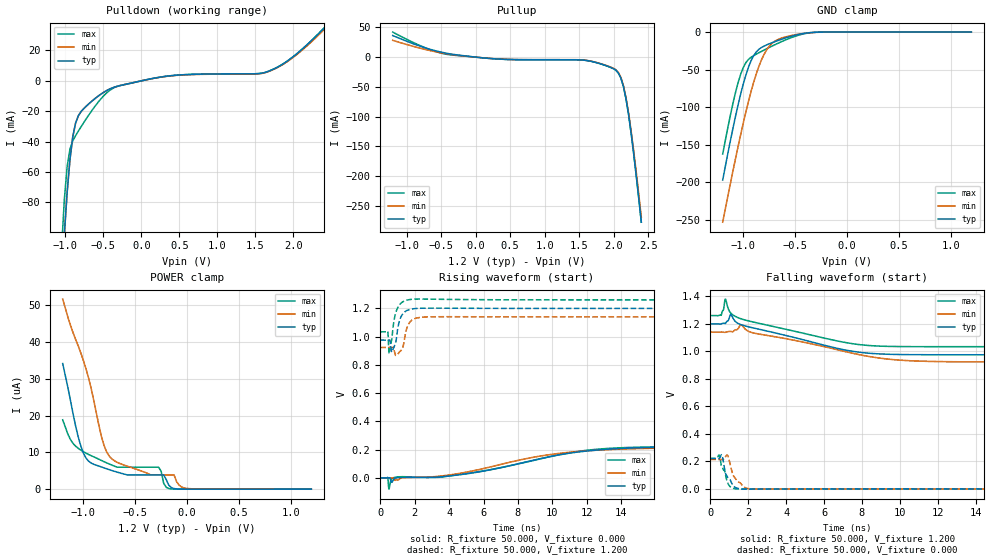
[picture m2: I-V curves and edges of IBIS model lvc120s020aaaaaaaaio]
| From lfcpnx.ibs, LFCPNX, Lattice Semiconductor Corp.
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[Model] lvc120s020aaaaaaaaio
Model_type I/O
Polarity   Non-Inverting
Enable   Active-Low
Vinl =  0.420V
Vinh =  0.780V
Vmeas =  0.600V
Cref =  0.0F
Rref =  1.000M
Vref =  0.0V
C_comp   5.000pF   4.000pF   5.500pF
[Temperature Range]   25.000   0.125k   -40.000
[Voltage Range]   1.200V   1.140V   1.260V
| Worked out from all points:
|   slope of the pulldown table from 0 to 0.18 V, typ, clamps not added: 97.6 ohm
|   slope of the pullup table from 0 to 0.18 V, typ, clamps not added: 88.3 ohm
|   GND clamp passes 1 mA (typ) near -0.37 V on its own axis
|   rising waveform, R_fixture 50.000, V_fixture 0.000: 20-80 % time 5.3ns typ, 5.17ns min, 5.23ns max; typ from 0 V to 0.221 V
|   rising waveform, R_fixture 50.000, V_fixture 1.200: 20-80 % time 300ps typ, 295ps min, 300ps max; typ from 0.975 V to 1.2 V
|   falling waveform, R_fixture 50.000, V_fixture 1.200: 20-80 % time 3.99ns typ, 4.41ns min, 4.36ns max; typ from 1.2 V to 0.975 V
|   falling waveform, R_fixture 50.000, V_fixture 0.000: 20-80 % time 406ps typ, 523ps min, 347ps max; typ from 0.221 V to 0 V
[GND_clamp]
|Voltage   I(typ)   I(min)   I(max)
-1.2V     -197mA     -253.2mA   -162.4mA
-1.125V   -144.2mA   -201.1mA   -110.1mA
-1.05V    -95.99mA   -151.4mA   -66.59mA
-1V       -68.36mA   -120.3mA   -46.7mA
-950mV    -46.27mA   -91.66mA   -36.22mA
-900mV    -31.17mA   -66.32mA   -31.23mA
-825mV    -20.42mA   -36.76mA   -25.67mA
-775mV    -17.01mA   -23.52mA   -22.16mA
-700mV    -12.93mA   -12.4mA    -17.08mA
-550mV    -6.031mA   -4.974mA   -8.039mA
-325mV    -407uA     -583.3uA   -420.6uA
1.2V      0A         0A         0A
[POWER_clamp]
|Voltage   I(typ)   I(min)   I(max)
-1.2V     34.12uA    51.64uA    18.84uA
-1.125V   24.08uA    44.51uA    13.48uA
-1.05V    14.15uA    38.9uA     11.09uA
-1V       9.797uA    34.91uA    10.18uA
-925mV    7.083uA    27.3uA     9.093uA
-825mV    6.019uA    14.19uA    7.781uA
-725mV    5.062uA    8.208uA    6.524uA
-275mV    3.872uA    3.86uA     5.968uA
-200mV    2.568uA    3.86uA     486.4nA
-150mV    410.4nA    3.86uA     46.48nA
0V        5.44nA     194.2nA    358.2pA
1.2V      0A         0A         0A
[Pulldown]
|Voltage   I(typ)   I(min)   I(max)
-1.2V     -291.4mA   -291.4mA   -309.1mA
-1.052V   -133.7mA   -133.7mA   -111mA
-1.015V   -101mA     -101mA     -78.13mA
-978mV    -73.37mA   -73.37mA   -56.36mA
-941mV    -51.83mA   -51.83mA   -44.93mA
-904mV    -36.89mA   -36.89mA   -39.52mA
-830mV    -22.91mA   -22.91mA   -33.01mA
-534mV    -8.79mA    -8.79mA    -11.89mA
-312mV    -3.504mA   -3.504mA   -3.577mA
243mV     2.389mA    2.317mA    2.389mA
1.612V    5.288mA    5.129mA    5.288mA
2.4V      34.47mA    33.43mA    34.47mA
[Pullup]
|Voltage   I(typ)   I(min)   I(max)
-1.2V     36.33mA    28.25mA    42.13mA
-745mV    16.17mA    13.34mA    16.53mA
-412mV    6.26mA     5.639mA    4.545mA
365mV     -3.465mA   -3.361mA   -3.465mA
1.549V    -4.954mA   -4.806mA   -4.954mA
2.03V     -21.89mA   -21.23mA   -21.89mA
2.104V    -35.19mA   -34.14mA   -35.19mA
2.141V    -49.43mA   -47.94mA   -49.43mA
2.178V    -69.96mA   -67.86mA   -69.96mA
2.215V    -96.3mA    -93.4mA    -96.3mA
2.289V    -162.1mA   -157.2mA   -162.1mA
2.4V      -277.9mA   -269.6mA   -277.9mA
[Ramp]
| variable   typ   min   max
dV/dt_r   0.133/5.402n   0.133/5.240n   0.133/5.329n
dV/dt_f   0.135/3.994n   0.130/4.414n   0.136/4.358n
R_load = 50.000
[Rising Waveform]
R_fixture = 50.000
V_fixture = 0.000
V_fixture_min = 0.000
V_fixture_max = 0.000
|  time   V(typ)   V(min)   V(max)
0s        24.94uV    -55.39uV   195.5uV
430ps     51.44uV    -176.3uV   3.184mV
504ps     14.05uV    -76.34uV   -80.32mV
643ps     -30.63mV   17.19uV    -11.12mV
855ps     -2.457mV   -17.33mV   3.521mV
3.643ns   8.516mV    14.33mV    6.479mV
6.04ns    48.42mV    66.92mV    50.26mV
9.01ns    127.9mV    148.2mV    125.7mV
11.92ns   188.8mV    190.4mV    194mV
20ns      221.1mV    214.2mV    221.4mV
[Rising Waveform]
R_fixture = 50.000
V_fixture = 1.200
V_fixture_min = 1.140
V_fixture_max = 1.260
|  time   V(typ)   V(min)   V(max)
0s        975.3mV    923.2mV    1.034V
431ps     975.3mV    923.1mV    1.038V
519ps     975.3mV    923.2mV    879mV
677ps     890mV      923.2mV    991.2mV
804ps     928.1mV    905.9mV    1.117V
955ps     1.003V     868.5mV    1.189V
1.237ns   1.147V     906.7mV    1.24V
1.546ns   1.185V     1.061V     1.258V
1.775ns   1.194V     1.11V      1.264V
20ns      1.2V       1.14V      1.26V
[Falling Waveform]
R_fixture = 50.000
V_fixture = 1.200
V_fixture_min = 1.140
V_fixture_max = 1.260
|  time   V(typ)   V(min)   V(max)
0s        1.2V       1.14V      1.26V
574ps     1.2V       1.14V      1.262V
704ps     1.205V     1.139V     1.307V
794ps     1.202V     1.138V     1.38V
1.08ns    1.267V     1.144V     1.278V
1.639ns   1.193V     1.192V     1.236V
2.202ns   1.172V     1.136V     1.215V
7.82ns    994.2mV    977mV      1.05V
11.52ns   975.4mV    926.9mV    1.034V
20ns      975.3mV    923.2mV    1.034V
[Falling Waveform]
R_fixture = 50.000
V_fixture = 0.000
V_fixture_min = 0.000
V_fixture_max = 0.000
|  time   V(typ)   V(min)   V(max)
0s        221.1mV    214.2mV    221.4mV
459ps     220.2mV    214.2mV    246.4mV
610ps     248mV      213.6mV    165mV
790ps     120.1mV    230mV      112.8mV
903ps     87.67mV    245.2mV    49.76mV
1.19ns    27.37mV    103.7mV    4.785mV
1.413ns   5.141mV    59.35mV    -636uV
1.853ns   -693.8uV   8.301mV    -1.816mV
2.333ns   -882.6uV   -637.4uV   -1.512mV
20ns      24.94uV    -55.39uV   195.5uV
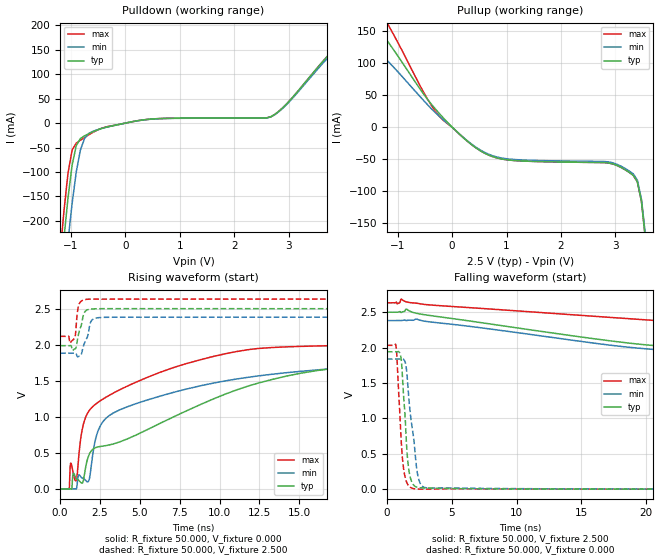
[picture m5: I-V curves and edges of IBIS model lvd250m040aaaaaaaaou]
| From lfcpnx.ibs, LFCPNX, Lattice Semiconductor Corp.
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[Model] lvd250m040aaaaaaaaou
Model_type Output
Polarity   Non-Inverting
Enable   Active-High
Vmeas =  1.250V
Cref =  0.0F
Rref =  1.000M
Vref =  0.0V
C_comp   5.000pF   4.000pF   5.500pF
[Temperature Range]   25.000   0.125k   -40.000
[Voltage Range]   2.500V   2.380V   2.630V
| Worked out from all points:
|   slope of the pulldown table from 0 to 0.375 V, typ, clamps not added: 52.3 ohm
|   slope of the pullup table from 0 to 0.375 V, typ, clamps not added: 13.2 ohm
|   rising waveform, R_fixture 50.000, V_fixture 0.000: 20-80 % time 12ns typ, 7.72ns min, 5.22ns max; typ from 0.001 V to 1.92 V
|   rising waveform, R_fixture 50.000, V_fixture 2.500: 20-80 % time 342ps typ, 406ps min, 152ps max; typ from 1.99 V to 2.5 V
|   falling waveform, R_fixture 50.000, V_fixture 2.500: 20-80 % time 11.9ns typ, 12.9ns min, 24.3ns max; typ from 2.5 V to 1.99 V
|   falling waveform, R_fixture 50.000, V_fixture 0.000: 20-80 % time 406ps typ, 634ps min, 379ps max; typ from 1.94 V to 0.001 V
[Pulldown]
|Voltage   I(typ)   I(min)   I(max)
-2.5V     -2.087A    -2.05A     -2.122A
-1.208V   -330.7mA   -414.1mA   -277.2mA
-1.132V   -238.1mA   -325.6mA   -182.4mA
-1.056V   -153.6mA   -241.4mA   -102.6mA
-980mV    -86mA      -164.4mA   -55.18mA
-904mV    -46.21mA   -100mA     -41.14mA
-752mV    -26.2mA    -31.37mA   -29.5mA
-600mV    -17.96mA   -17.01mA   -19.2mA
464mV     8.134mA    7.89mA     8.134mA
2.668V    12.76mA    12.38mA    12.76mA
4.112V    178.7mA    173.3mA    178.7mA
5V        197.1mA    191.2mA    197.1mA
[Pullup]
|Voltage   I(typ)   I(min)   I(max)
-2.5V     189.4mA    141.7mA    232mA
-1.84V    186.8mA    140.8mA    228.1mA
-1.384V   155.4mA    119.1mA    188.3mA
-1.156V   130.2mA    100.6mA    156.5mA
-320mV    29.46mA    23.51mA    26.02mA
592mV     -40.38mA   -39.17mA   -40.38mA
1.124V    -51.9mA    -50.35mA   -51.9mA
2.948V    -57.25mA   -55.53mA   -57.25mA
3.404V    -85.21mA   -82.65mA   -85.21mA
3.48V     -116.2mA   -112.7mA   -116.2mA
3.556V    -176.5mA   -171.2mA   -176.5mA
5V        -2.101A    -2.038A    -2.101A
[Ramp]
| variable   typ   min   max
dV/dt_r   1.154/11.967n   1.103/7.727n   1.219/5.294n
dV/dt_f   0.308/11.994n   0.313/13.083n   0.310/24.253n
R_load = 50.000
[Rising Waveform]
R_fixture = 50.000
V_fixture = 0.000
V_fixture_min = 0.000
V_fixture_max = 0.000
|  time   V(typ)   V(min)   V(max)
0s        531.4uV    878.5uV    348.5uV
570ps     700.4uV    911.2uV    2.05mV
670ps     1.336mV    602.2uV    358.2mV
1.01ns    136.7mV    413.3uV    113.3mV
1.39ns    79.99mV    151mV      831.9mV
1.8ns     466mV      114.5mV    1.079V
2.52ns    588.9mV    875.6mV    1.223V
13.3ns    1.518V     1.591V     1.962V
39.57ns   1.904V     1.807V     2.011V
200ns     1.924V     1.839V     2.032V
[Rising Waveform]
R_fixture = 50.000
V_fixture = 2.500
V_fixture_min = 2.380
V_fixture_max = 2.630
|  time   V(typ)   V(min)   V(max)
0s        1.987V     1.882V     2.117V
540ps     1.987V     1.882V     2.117V
620ps     1.987V     1.882V     2.023V
910ps     1.942V     1.883V     2.096V
960ps     1.945V     1.883V     2.14V
1.1ns     2.088V     1.833V     2.478V
1.28ns    2.242V     1.848V     2.595V
1.54ns    2.454V     2.03V      2.625V
2.01ns    2.496V     2.345V     2.633V
200ns     2.5V       2.382V     2.633V
[Falling Waveform]
R_fixture = 50.000
V_fixture = 2.500
V_fixture_min = 2.380
V_fixture_max = 2.630
|  time   V(typ)   V(min)   V(max)
0s        2.5V       2.382V     2.633V
800ps     2.5V       2.382V     2.619V
1.1ns     2.496V     2.382V     2.686V
1.5ns     2.544V     2.382V     2.646V
2.86ns    2.465V     2.375V     2.611V
16.9ns    2.103V     2.041V     2.431V
25.5ns    1.991V     1.926V     2.321V
38.87ns   1.987V     1.884V     2.16V
47.58ns   1.987V     1.883V     2.119V
200ns     1.987V     1.882V     2.117V
[Falling Waveform]
R_fixture = 50.000
V_fixture = 0.000
V_fixture_min = 0.000
V_fixture_max = 0.000
|  time   V(typ)   V(min)   V(max)
0s        1.941V     1.839V     2.032V
700ps     1.941V     1.839V     2.026V
1.1ns     1.841V     1.839V     698.2mV
1.42ns    978.1mV    1.79V      160.2mV
1.56ns    507.5mV    1.601V     83.55mV
1.74ns    222.3mV    1.187V     35.27mV
2.3ns     28.6mV     291.1mV    2.224mV
2.67ns    18.84mV    53.48mV    275.2uV
3.28ns    15.12mV    16.14mV    401uV
200ns     531.9uV    878.5uV    348.5uV
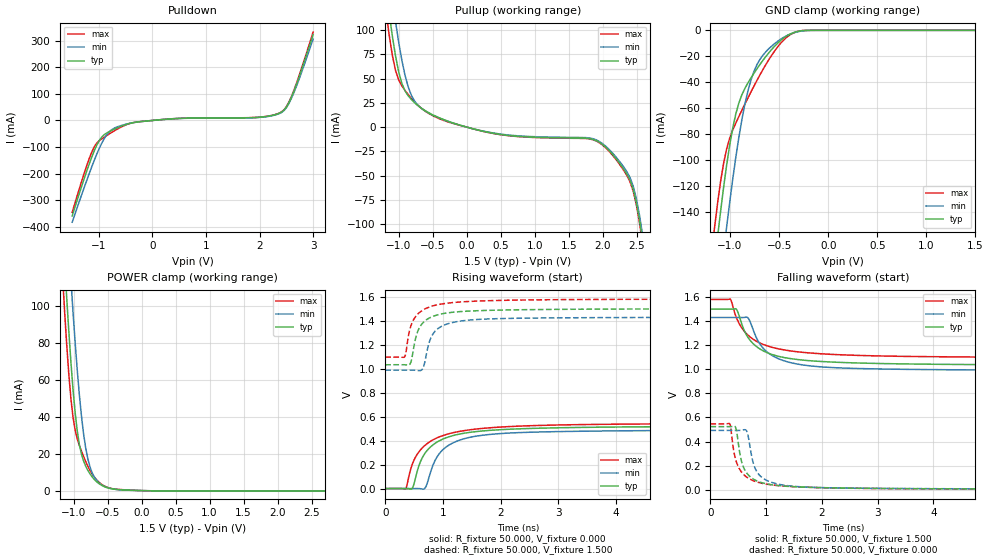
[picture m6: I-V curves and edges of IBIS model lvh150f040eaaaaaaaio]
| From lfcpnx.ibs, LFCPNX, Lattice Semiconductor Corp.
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[Model] lvh150f040eaaaaaaaio
Model_type I/O
Polarity   Non-Inverting
Enable   Active-Low
Vinl =  0.375V
Vinh =  1.125V
Vmeas =  0.750V
Cref =  0.0F
Rref =  1.000M
Vref =  0.0V
C_comp   5.000pF   4.000pF   5.500pF
[Temperature Range]   25.000   0.125k   -40.000
[Voltage Range]   1.500V   1.430V   1.580V
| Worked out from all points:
|   slope of the pulldown table from 0 to 0.225 V, typ, clamps not added: 54.8 ohm
|   slope of the pullup table from 0 to 0.225 V, typ, clamps not added: 56 ohm
|   GND clamp passes 1 mA (typ) near -0.32 V on its own axis
|   POWER clamp passes 1 mA (typ) near -0.45 V on its own axis
|   rising waveform, R_fixture 50.000, V_fixture 0.000: 20-80 % time 484ps typ, 460ps min, 544ps max; typ from 0.005 V to 0.524 V
|   rising waveform, R_fixture 50.000, V_fixture 1.500: 20-80 % time 234ps typ, 239ps min, 259ps max; typ from 1.03 V to 1.5 V
|   falling waveform, R_fixture 50.000, V_fixture 1.500: 20-80 % time 536ps typ, 520ps min, 594ps max; typ from 1.5 V to 1.03 V
|   falling waveform, R_fixture 50.000, V_fixture 0.000: 20-80 % time 220ps typ, 226ps min, 243ps max; typ from 0.524 V to 0.005 V
[GND_clamp]
|Voltage   I(typ)   I(min)   I(max)
-1.5V     -437mA     -482.5mA   -410.7mA
-1.159V   -180.3mA   -233.3mA   -152.2mA
-1.128V   -159.5mA   -212mA     -133.3mA
-1.097V   -139.6mA   -191.2mA   -116.5mA
-1.035V   -103.7mA   -151.3mA   -91.23mA
-973mV    -75.24mA   -114.6mA   -76.75mA
-911mV    -56.05mA   -82.58mA   -66.41mA
-787mV    -36.61mA   -38.2mA    -47.39mA
-663mV    -22.9mA    -18.92mA   -29.92mA
-477mV    -7.274mA   -6.461mA   -9.278mA
-260mV    -227.6uA   -429.8uA   -148.6uA
1.5V      0A         0A         0A
[POWER_clamp]
|Voltage   I(typ)   I(min)   I(max)
-1.5V     391.3mA    429.6mA    369.7mA
-1.166V   144.6mA    192.2mA    117.1mA
-1.135V   124.2mA    171.8mA    97.3mA
-1.104V   104.7mA    152mA      79.15mA
-1.042V   69.75mA    114.3mA    49.91mA
-1.011V   54.95mA    96.78mA    39.84mA
-949mV    32.47mA    65.46mA    28.02mA
-887mV    19.82mA    40.53mA    21.37mA
-825mV    13.31mA    23.23mA    15.79mA
-732mV    7.53mA     9.888mA    9.145mA
-608mV    3.278mA    3.592mA    3.895mA
3V        -183uA     -190.7uA   -185.3uA
[Pulldown]
|Voltage   I(typ)   I(min)   I(max)
-1.5V     -358.2mA   -381.8mA   -344.9mA
-1.224V   -187.6mA   -222.6mA   -167mA
-1.086V   -112.9mA   -148.8mA   -98.5mA
-948mV    -62.28mA   -85.2mA    -69.02mA
-764mV    -37.5mA    -35.09mA   -45.15mA
-258mV    -5.249mA   -5.157mA   -4.87mA
1.95V     11.37mA    10.8mA     11.71mA
2.364V    26.55mA    25.22mA    27.35mA
2.502V    50.62mA    48.08mA    52.13mA
2.594V    86.8mA     82.5mA     89.4mA
2.732V    159.4mA    151.4mA    164.2mA
3V        321.9mA    305.8mA    331.6mA
[Pullup]
|Voltage   I(typ)   I(min)   I(max)
-1.5V     334.2mA    366.8mA    315.2mA
-1.186V   140.5mA    179.9mA    117.2mA
-1.14V    115.6mA    154.7mA    93.3mA
-1.048V   72.68mA    107.9mA    57.95mA
-956mV    44.92mA    68.74mA    42.37mA
-864mV    32.38mA    41.6mA     33.55mA
-588mV    15.88mA    15.55mA    15.32mA
424mV     -6.746mA   -6.408mA   -6.948mA
1.896V    -13.58mA   -12.9mA    -13.99mA
2.402V    -54.62mA   -51.89mA   -56.26mA
2.586V    -116.3mA   -110.5mA   -119.8mA
3V        -369.7mA   -351.2mA   -380.8mA
[Ramp]
| variable   typ   min   max
dV/dt_r   0.311/0.493n   0.292/0.462n   0.332/0.551n
dV/dt_f   0.280/0.532n   0.264/0.520n   0.290/0.596n
R_load = 50.000
[Rising Waveform]
R_fixture = 50.000
V_fixture = 0.000
V_fixture_min = 0.000
V_fixture_max = 0.000
|  time   V(typ)   V(min)   V(max)
0s        4.663mV    4.769mV    4.349mV
351ps     4.928mV    4.827mV    1.294mV
457ps     1.861mV    4.813mV    191.3mV
597ps     213.2mV    4.245mV    318.6mV
677ps     290.3mV    3.446mV    359.2mV
856ps     378.3mV    231.4mV    417.1mV
988ps     413.9mV    323.1mV    443.7mV
1.557ns   477.6mV    439mV      498.6mV
3.321ns   512.7mV    480.9mV    536.2mV
10ns      523.5mV    492.3mV    546.5mV
[Rising Waveform]
R_fixture = 50.000
V_fixture = 1.500
V_fixture_min = 1.430
V_fixture_max = 1.580
|  time   V(typ)   V(min)   V(max)
0s        1.034V     989.4mV    1.097V
336ps     1.034V     989.5mV    1.101V
424ps     1.038V     989.5mV    1.326V
537ps     1.275V     988.1mV    1.442V
627ps     1.369V     990mV      1.481V
766ps     1.423V     1.227V     1.515V
827ps     1.437V     1.291V     1.524V
1.156ns   1.47V      1.384V     1.55V
2.427ns   1.492V     1.422V     1.573V
10ns      1.5V       1.43V      1.58V
[Falling Waveform]
R_fixture = 50.000
V_fixture = 1.500
V_fixture_min = 1.430
V_fixture_max = 1.580
|  time   V(typ)   V(min)   V(max)
0s        1.5V       1.43V      1.58V
356ps     1.5V       1.43V      1.582V
477ps     1.49V      1.43V      1.417V
657ps     1.277V     1.432V     1.291V
857ps     1.178V     1.233V     1.225V
987ps     1.144V     1.155V     1.199V
1.246ns   1.105V     1.083V     1.167V
1.619ns   1.078V     1.039V     1.142V
3.416ns   1.045V     999.8mV    1.107V
10ns      1.034V     989.4mV    1.097V
[Falling Waveform]
R_fixture = 50.000
V_fixture = 0.000
V_fixture_min = 0.000
V_fixture_max = 0.000
|  time   V(typ)   V(min)   V(max)
0s        523.5mV    492.3mV    546.5mV
346ps     523.2mV    492mV      547.1mV
444ps     523.6mV    492.2mV    265.5mV
547ps     255mV      493.1mV    153.2mV
637ps     147.4mV    495mV      109.2mV
757ps     92mV       241.4mV    76.83mV
817ps     76.38mV    162.2mV    66.45mV
1.137ns   38.39mV    55.03mV    37.78mV
2.407ns   13.61mV    13.6mV     12.6mV
10ns      4.663mV    4.769mV    4.349mV
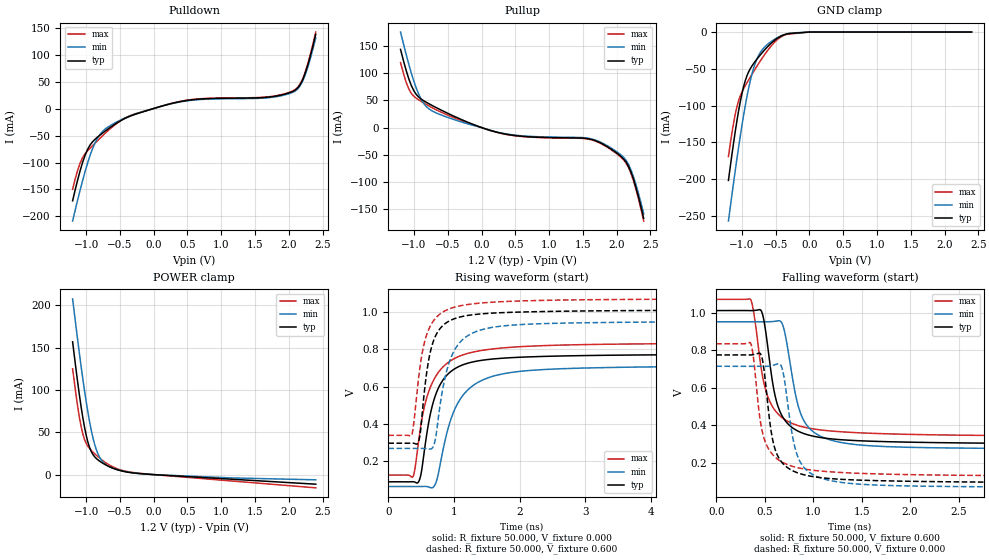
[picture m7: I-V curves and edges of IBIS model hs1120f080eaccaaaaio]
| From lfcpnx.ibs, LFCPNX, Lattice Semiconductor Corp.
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|Model hs1120f080eaccaaaaio
[Model] hs1120f080eaccaaaaio
| Clamp models do not include dynamic input termination. Please refer to
| the hs1120axxxeaccaaaain model for input termination.
Model_type I/O
Polarity   Non-Inverting
Enable   Active-Low
Vinl =  0.500V
Vinh =  0.700V
Vmeas =  0.600V
Cref =  20.000pF
Rref =  50.000
Vref =  0.600V
C_comp   5.000pF   4.000pF   5.500pF
[Temperature Range]   25.000   0.125k   -40.000
[Voltage Range]   1.200V   1.140V   1.260V
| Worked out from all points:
|   slope of the pulldown table from 0 to 0.18 V, typ, clamps not added: 27.4 ohm
|   slope of the pullup table from 0 to 0.18 V, typ, clamps not added: 25.5 ohm
|   GND clamp passes 1 mA (typ) near -0.14 V on its own axis
|   POWER clamp passes 1 mA (typ) near -0.17 V on its own axis
|   rising waveform, R_fixture 50.000, V_fixture 0.000: 20-80 % time 298ps typ, 419ps min, 351ps max; typ from 0.091 V to 0.775 V
|   rising waveform, R_fixture 50.000, V_fixture 0.600: 20-80 % time 202ps typ, 289ps min, 226ps max; typ from 0.298 V to 1.01 V
|   falling waveform, R_fixture 50.000, V_fixture 0.600: 20-80 % time 171ps typ, 190ps min, 188ps max; typ from 1.01 V to 0.298 V
|   falling waveform, R_fixture 50.000, V_fixture 0.000: 20-80 % time 137ps typ, 156ps min, 148ps max; typ from 0.775 V to 0.091 V
[Pulldown]
|Voltage   I(typ)   I(min)   I(max)
-1.2V     -171mA     -208.4mA   -149.8mA
-1.089V   -115.3mA   -151.3mA   -101.1mA
-978mV    -75.7mA    -101mA     -78.43mA
-867mV    -56.88mA   -63.48mA   -64.1mA
-719mV    -41.92mA   -38.16mA   -46.06mA
-386mV    -16.16mA   -15.49mA   -15.15mA
317mV     10.85mA    10.31mA    11.18mA
1.686V    20.95mA    19.91mA    21.58mA
2.056V    31.4mA     29.83mA    32.34mA
2.204V    52.73mA    50.09mA    54.31mA
2.278V    78.8mA     74.9mA     81.2mA
2.4V      137.6mA    130.7mA    141.7mA
[Pullup]
|Voltage   I(typ)   I(min)   I(max)
-1.2V     143.8mA    175.7mA    119.5mA
-1.115V   104.4mA    133.7mA    82.8mA
-1.004V   67.92mA    85.7mA     57.67mA
-893mV    52.22mA    51.65mA    48.03mA
-782mV    43.96mA    34.65mA    39.94mA
-227mV    10.98mA    7.588mA    9.596mA
254mV     -9.406mA   -8.935mA   -9.688mA
1.512V    -19.59mA   -18.61mA   -20.17mA
1.771V    -28.88mA   -27.43mA   -29.74mA
2.141V    -63.74mA   -60.55mA   -65.65mA
2.252V    -96.2mA    -91.4mA    -99.1mA
2.4V      -166.9mA   -158.6mA   -171.9mA
[GND_clamp]
|Voltage   I(typ)   I(min)   I(max)
-1.2V     -201.8mA   -257mA     -169.4mA
-1.125V   -151.4mA   -205.6mA   -124.4mA
-1.05V    -107.4mA   -157mA     -93.36mA
-975mV    -74.07mA   -112.9mA   -77.04mA
-925mV    -59.28mA   -87.24mA   -68.87mA
-875mV    -49.6mA    -65.58mA   -61.06mA
-825mV    -42.58mA   -48.49mA   -53.44mA
-750mV    -33.57mA   -31.23mA   -42.41mA
-600mV    -18.06mA   -15.21mA   -22.68mA
-375mV    -3.74mA    -3.594mA   -4.332mA
0V        0A         0A         0A
2.4V      0A         0A         0A
[POWER_clamp]
|Voltage   I(typ)   I(min)   I(max)
-1.2V     156.9mA    207.6mA    125mA
-1.125V   109.1mA    159mA      80.51mA
-1.075V   80.57mA    128.3mA    57.13mA
-1.025V   56.63mA    99.87mA    41.73mA
-975mV    38.74mA    74.4mA     33.51mA
-900mV    23.86mA    43.88mA    26.68mA
-850mV    19.08mA    29.7mA     22.97mA
-775mV    14.57mA    17.25mA    17.9mA
-700mV    11.09mA    11.42mA    13.53mA
-450mV    3.875mA    4.163mA    4.676mA
-125mV    735.3uA    624.3uA    974.1uA
2.4V      -11.3mA    -6.156mA   -15.63mA
[Ramp]
| variable   typ   min   max
dV/dt_r   0.410/0.301n   0.383/0.423n   0.425/0.357n
dV/dt_f   0.388/0.249n   0.375/0.265n   0.390/0.295n
R_load = 50.000
[Rising Waveform]
R_fixture = 50.000
V_fixture = 0.000
V_fixture_min = 0.000
V_fixture_max = 0.000
|  time   V(typ)   V(min)   V(max)
0s        90.91mV    65.64mV    126.8mV
371ps     91.54mV    65.65mV    117.2mV
457ps     89.22mV    65.68mV    299.8mV
497ps     132.2mV    65.83mV    398.5mV
554ps     271.9mV    66.21mV    500.9mV
697ps     533.1mV    67.07mV    641.1mV
987ps     691.2mV    459.5mV    748mV
1.317ns   735.6mV    613.5mV    788.1mV
2.62ns    765.1mV    696.7mV    823.5mV
10ns      775mV      714.3mV    834.4mV
[Rising Waveform]
R_fixture = 50.000
V_fixture = 0.600
V_fixture_min = 0.571
V_fixture_max = 0.631
|  time   V(typ)   V(min)   V(max)
0s        297.8mV    269.9mV    339.8mV
354ps     298.1mV    269.9mV    341mV
457ps     303.2mV    270mV      635.4mV
547ps     569.6mV    269.8mV    833.4mV
677ps     835.5mV    275.7mV    948.2mV
886ps     943.9mV    682.5mV    1.011V
1.087ns   973.6mV    836.9mV    1.034V
1.496ns   992.9mV    912.6mV    1.051V
2.337ns   1.003V     938.3mV    1.063V
10ns      1.012V     951.7mV    1.071V
[Falling Waveform]
R_fixture = 50.000
V_fixture = 0.600
V_fixture_min = 0.571
V_fixture_max = 0.631
|  time   V(typ)   V(min)   V(max)
0s        1.012V     951.7mV    1.071V
356ps     1.011V     951.6mV    1.069V
467ps     1.008V     951.6mV    691.6mV
520ps     862.3mV    951.5mV    570mV
598ps     578.9mV    953.9mV    484.8mV
671ps     457.4mV    950.2mV    443.6mV
860ps     364.3mV    477.9mV    395.5mV
1.03ns    338.3mV    354.1mV    377.9mV
2.23ns    307.3mV    279.6mV    348.7mV
10ns      297.8mV    269.9mV    339.8mV
[Falling Waveform]
R_fixture = 50.000
V_fixture = 0.000
V_fixture_min = 0.000
V_fixture_max = 0.000
|  time   V(typ)   V(min)   V(max)
0s        775mV      714.3mV    834.4mV
356ps     774.8mV    714mV      836.1mV
456ps     781.3mV    714.2mV    417.4mV
486ps     720.2mV    713.8mV    342.6mV
576ps     337.2mV    718.4mV    246.5mV
660ps     213.1mV    724.5mV    208.8mV
822ps     149.1mV    261.6mV    175.3mV
970ps     128.1mV    144.7mV    161.4mV
2.142ns   99.51mV    74.41mV    134.9mV
10ns      90.91mV    65.64mV    126.8mV
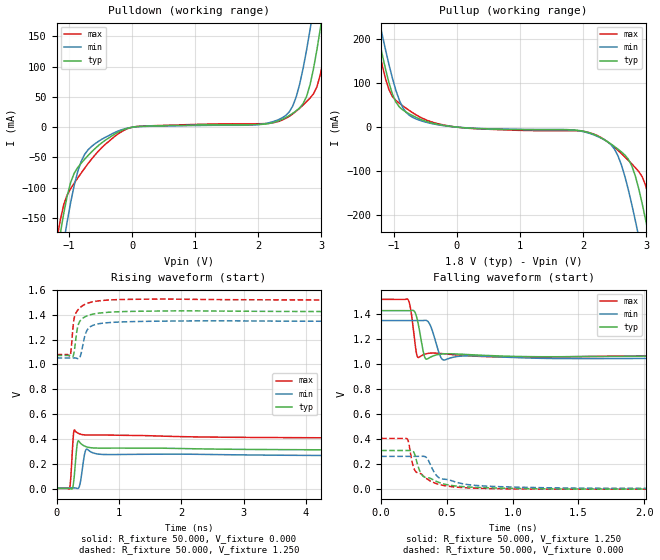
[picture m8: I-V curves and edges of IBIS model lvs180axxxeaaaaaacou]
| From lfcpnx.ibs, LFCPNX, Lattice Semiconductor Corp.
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[Model] lvs180axxxeaaaaaacou
Model_type Output
Polarity   Non-Inverting
Enable   Active-High
Vmeas =  1.250V
Cref =  3.000pF
Rref =  50.000
Vref =  1.250V
C_comp   5.000pF   4.000pF   5.500pF
[Temperature Range]   25.000   0.125k   -40.000
[Voltage Range]   1.800V   1.710V   1.890V
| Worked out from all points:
|   slope of the pulldown table from 0 to 0.27 V, typ, clamps not added: 142 ohm
|   slope of the pullup table from 0 to 0.27 V, typ, clamps not added: 91.7 ohm
|   rising waveform, R_fixture 50.000, V_fixture 0.000: 20-80 % time 32.3ps typ, 44ps min, 28.4ps max; typ from 0.004 V to 0.309 V
|   rising waveform, R_fixture 50.000, V_fixture 1.250: 20-80 % time 89ps typ, 100ps min, 87.7ps max; typ from 1.07 V to 1.42 V
|   falling waveform, R_fixture 50.000, V_fixture 1.250: 20-80 % time 37.5ps typ, 51.3ps min, 31.9ps max; typ from 1.42 V to 1.07 V
|   falling waveform, R_fixture 50.000, V_fixture 0.000: 20-80 % time 155ps typ, 200ps min, 132ps max; typ from 0.309 V to 0.003 V
[Pulldown]
|Voltage   I(typ)   I(min)   I(max)
-1.8V     -681.2mA   -716.3mA   -662.4mA
-1.195V   -212.7mA   -264mA     -185.8mA
-1.085V   -141.9mA   -189.7mA   -127.6mA
-975mV    -90.96mA   -123.8mA   -101.3mA
-755mV    -53.04mA   -45.02mA   -67.87mA
-150mV    -4.68mA    -3.708mA   -6.333mA
2.49V     19.13mA    25.2mA     17.88mA
2.655V    31.84mA    70.95mA    31.23mA
2.82V     70.16mA    161mA      48.03mA
2.985V    164.3mA    271.4mA    87.85mA
3.15V     282.5mA    389.7mA    190.9mA
3.6V      631.9mA    726.6mA    545.1mA
[Pullup]
|Voltage   I(typ)   I(min)   I(max)
-1.8V     633.7mA    660.1mA    620.6mA
-1.35V    284.7mA    326.6mA    260.5mA
-1.24V    204.9mA    249.2mA    179.6mA
-1.02V    75.12mA    110.9mA    69.42mA
-745mV    29.49mA    26.13mA    37.05mA
25mV      -288.8uA   -173.9uA   -376.6uA
2.17V     -16.09mA   -17.47mA   -15.69mA
2.555V    -49.99mA   -64.93mA   -52.72mA
2.885V    -139.9mA   -249mA     -100.7mA
2.995V    -211.2mA   -327mA     -132.9mA
3.16V     -332.6mA   -448.7mA   -236.3mA
3.6V      -680.1mA   -784.7mA   -587mA
[Ramp]
| variable   typ   min   max
dV/dt_r   0.188/32.395p   0.158/43.981p   0.247/28.489p
dV/dt_f   0.124/26.621p   91.486m/33.641p   0.170/23.531p
R_load = 50.000
[Rising Waveform]
R_fixture = 50.000
V_fixture = 0.000
V_fixture_min = 0.000
V_fixture_max = 0.000
|  time   V(typ)   V(min)   V(max)
0s        3.672mV    7.239mV    3.406mV
208ps     3.838mV    7.242mV    2.205mV
227ps     1.515mV    7.228mV    78.94mV
256ps     5.395mV    7.212mV    324.4mV
287ps     117mV      7.351mV    473.7mV
342ps     380.8mV    2.764mV    448.3mV
382ps     368mV      52.09mV    439.9mV
454ps     342.9mV    288.4mV    433.5mV
488ps     336.6mV    319mV      432.7mV
10ns      309.2mV    262.6mV    405.6mV
[Rising Waveform]
R_fixture = 50.000
V_fixture = 1.250
V_fixture_min = 1.188
V_fixture_max = 1.313
|  time   V(typ)   V(min)   V(max)
0s        1.073V     1.052V     1.08V
219ps     1.072V     1.052V     1.072V
234ps     1.068V     1.052V     1.118V
261ps     1.064V     1.052V     1.282V
282ps     1.099V     1.052V     1.368V
325ps     1.263V     1.049V     1.425V
354ps     1.327V     1.046V     1.445V
498ps     1.393V     1.282V     1.492V
756ps     1.417V     1.333V     1.515V
10ns      1.424V     1.345V     1.517V
[Falling Waveform]
R_fixture = 50.000
V_fixture = 1.250
V_fixture_min = 1.188
V_fixture_max = 1.313
|  time   V(typ)   V(min)   V(max)
0s        1.424V     1.345V     1.514V
207ps     1.423V     1.345V     1.508V
228ps     1.424V     1.345V     1.415V
254ps     1.417V     1.345V     1.199V
282ps     1.319V     1.345V     1.05V
339ps     1.04V      1.346V     1.079V
374ps     1.052V     1.307V     1.085V
448ps     1.077V     1.066V     1.083V
477ps     1.079V     1.03V      1.08V
10ns      1.073V     1.052V     1.076V
[Falling Waveform]
R_fixture = 50.000
V_fixture = 0.000
V_fixture_min = 0.000
V_fixture_max = 0.000
|  time   V(typ)   V(min)   V(max)
0s        309.2mV    262.6mV    405.6mV
198ps     309.4mV    262.6mV    402.7mV
255ps     280.1mV    262.6mV    154.5mV
309ps     116.9mV    263mV      118.8mV
345ps     93.81mV    253.1mV    86.23mV
378ps     86.03mV    188.9mV    64.48mV
445ps     52.93mV    89.83mV    37.91mV
689ps     17.2mV     33.98mV    10.24mV
1.699ns   2.21mV     8.375mV    1.472mV
10ns      2.716mV    6.71mV     2.136mV
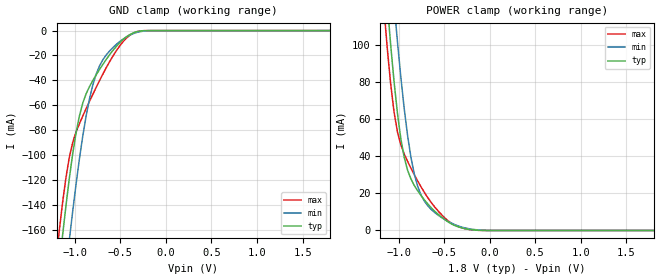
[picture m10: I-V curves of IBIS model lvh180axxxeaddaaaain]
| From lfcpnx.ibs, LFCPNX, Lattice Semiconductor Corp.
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|Model lvh180axxxeaddaaaain
[Model] lvh180axxxeaddaaaain
Model_type Input
Polarity   Non-Inverting
Enable   Active-High
Vinl =  0.630V
Vinh =  1.170V
C_comp   5.000pF   4.000pF   5.500pF
[Temperature Range]   25.000   0.125k   -40.000
[Voltage Range]   1.800V   1.710V   1.890V
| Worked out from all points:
|   GND clamp passes 1 mA (typ) near -0.32 V on its own axis
|   POWER clamp passes 1 mA (typ) near -0.27 V on its own axis
[GND_clamp]
|Voltage   I(typ)   I(min)   I(max)
-1.8V     -677.5mA   -713mA     -658.3mA
-1.171V   -189.9mA   -242.9mA   -161.4mA
-1.134V   -164.8mA   -217.4mA   -138.4mA
-1.06V    -118.9mA   -168.5mA   -102mA
-1.023V   -99.16mA   -145.4mA   -89.98mA
-949mV    -68.55mA   -103.1mA   -74.79mA
-838mV    -44.93mA   -54.66mA   -56.82mA
-764mV    -35.44mA   -34.74mA   -45.46mA
-616mV    -19.23mA   -16.23mA   -24.76mA
-394mV    -3.128mA   -3.569mA   -3.61mA
-246mV    -140.7uA   -457.2uA   -76.91uA
1.8V      0A         0A         0A
[POWER_clamp]
|Voltage   I(typ)   I(min)   I(max)
-1.8V     630.7mA    657.6mA    617.2mA
-1.16V    145.7mA    191.9mA    120mA
-1.123V   122.1mA    167.9mA    98mA
-1.086V   100.1mA    144.7mA    78.99mA
-1.049V   80.33mA    122.6mA    63.89mA
-1.012V   63.31mA    101.9mA    53.2mA
-938mV    39.5mA     65.89mA    41.31mA
-864mV    27.77mA    39.53mA    33.58mA
-790mV    21.38mA    23.82mA    26.71mA
-457mV    4.636mA    4.921mA    5.201mA
-124mV    126.2uA    290uA      82.78uA
1.8V      0A         0A         0A
